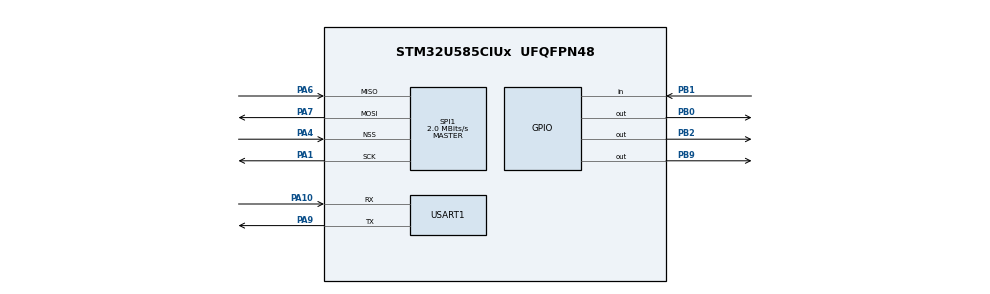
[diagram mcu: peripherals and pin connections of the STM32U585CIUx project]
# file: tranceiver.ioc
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CORTEX_M33_NS.userName=CORTEX_M33
Mcu.Family=STM32U5
Mcu.Name=STM32U585CIUx
Mcu.Package=UFQFPN48
NVIC.PriorityGroup=NVIC_PRIORITYGROUP_4
PA1.Mode=Full_Duplex_Master
PA1.Signal=SPI1_SCK
PA10.Mode=Asynchronous
PA10.Signal=USART1_RX
PA4.Mode=NSS_Signal_Hard_Input
PA4.Signal=SPI1_NSS
PA6.Mode=Full_Duplex_Master
PA6.Signal=SPI1_MISO
PA7.Mode=Full_Duplex_Master
PA7.Signal=SPI1_MOSI
PA9.Mode=Asynchronous
PA9.Signal=USART1_TX
PB0.Signal=GPIO_Output
PB1.Signal=GPIO_Input
PB2.Signal=GPIO_Output
PB9.Signal=GPIO_Output
PC14-OSC32_IN\ (PC14).Mode=LSE-External-Oscillator
PC14-OSC32_IN\ (PC14).Signal=RCC_OSC32_IN
PC15-OSC32_OUT\ (PC15).Mode=LSE-External-Oscillator
PC15-OSC32_OUT\ (PC15).Signal=RCC_OSC32_OUT
PH0-OSC_IN\ (PH0).Mode=HSE-External-Oscillator
PH0-OSC_IN\ (PH0).Signal=RCC_OSC_IN
PH1-OSC_OUT\ (PH1).Mode=HSE-External-Oscillator
PH1-OSC_OUT\ (PH1).Signal=RCC_OSC_OUT
ProjectManager.HeapSize=0x200
ProjectManager.StackSize=0x400
ProjectManager.TargetToolchain=EWARM V9.20
RCC.ADCFreq_Value=16000000
RCC.EPOD_VALUE=4000000
RCC.HSE_VALUE=16000000
RCC.HSI48_VALUE=48000000
RCC.HSI_VALUE=16000000
RCC.LSIDIV_VALUE=32000
RCC.MSI_VALUE=4000000
RCC.USBFreq_Value=48000000
RCC.VCOOutputFreq_Value=516000000
SPI1.CalculateBaudRate=2.0 MBits/s
SPI1.Direction=SPI_DIRECTION_2LINES
SPI1.Mode=SPI_MODE_MASTER
SPI1.VirtualNSS=VM_NSSHARD
SPI1.VirtualType=VM_MASTER
USART1.VirtualMode-Asynchronous=VM_ASYNC
VP_ICACHE_VS_ICACHE.Mode=DefaultMode
VP_LPBAMQUEUE_VS_QUEUE.Mode=QUEUEMODE
VP_LPBAM_VS_SIG1.Mode=SmartRun
VP_LPBAM_VS_SIG4.Mode=LPDMA1
VP_MEMORYMAP_VS_MEMORYMAP.Mode=CurAppReg
VP_PWR_VS_SECSignals.Mode=Security/Privilege
board=custom

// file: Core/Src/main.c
/* USER CODE BEGIN Header */
/**
  ******************************************************************************
  * @file           : main.c
  * @brief          : Main program body
  ******************************************************************************
  * @attention
  *
  * Copyright (c) 2026 STMicroelectronics.
  * All rights reserved.
  *
  * This software is licensed under terms that can be found in the LICENSE file
  * in the root directory of this software component.
  * If no LICENSE file comes with this software, it is provided AS-IS.
  *
  ******************************************************************************
  */
/* USER CODE END Header */
#include "main.h"

SPI_HandleTypeDef hspi1;

UART_HandleTypeDef huart1;

void SystemClock_Config(void);
static void MX_GPIO_Init(void);
static void MX_SPI1_Init(void);
static void MX_USART1_UART_Init(void);
static void MX_ICACHE_Init(void);

int main(void)
{

  /* MCU Configuration--------------------------------------------------------*/

  /* Reset of all peripherals, Initializes the Flash interface and the Systick. */
  HAL_Init();

  /* Configure the system clock */
  SystemClock_Config();

  /* Initialize all configured peripherals */
  MX_GPIO_Init();
  MX_SPI1_Init();
  MX_USART1_UART_Init();
  MX_ICACHE_Init();

  /* Infinite loop */
  while (1)
  {

  }
}

void SystemClock_Config(void)
{
  RCC_OscInitTypeDef RCC_OscInitStruct = {0};
  RCC_ClkInitTypeDef RCC_ClkInitStruct = {0};

  /** Configure the main internal regulator output voltage
  */
  if (HAL_PWREx_ControlVoltageScaling(PWR_REGULATOR_VOLTAGE_SCALE4) != HAL_OK)
  {
    Error_Handler();
  }

  /** Initializes the CPU, AHB and APB buses clocks
  */
  RCC_OscInitStruct.OscillatorType = RCC_OSCILLATORTYPE_MSI;
  RCC_OscInitStruct.MSIState = RCC_MSI_ON;
  RCC_OscInitStruct.MSICalibrationValue = RCC_MSICALIBRATION_DEFAULT;
  RCC_OscInitStruct.MSIClockRange = RCC_MSIRANGE_4;
  RCC_OscInitStruct.PLL.PLLState = RCC_PLL_NONE;
  if (HAL_RCC_OscConfig(&RCC_OscInitStruct) != HAL_OK)
  {
    Error_Handler();
  }

  /** Initializes the CPU, AHB and APB buses clocks
  */
  RCC_ClkInitStruct.ClockType = RCC_CLOCKTYPE_HCLK|RCC_CLOCKTYPE_SYSCLK
                              |RCC_CLOCKTYPE_PCLK1|RCC_CLOCKTYPE_PCLK2
                              |RCC_CLOCKTYPE_PCLK3;
  RCC_ClkInitStruct.SYSCLKSource = RCC_SYSCLKSOURCE_MSI;
  RCC_ClkInitStruct.AHBCLKDivider = RCC_SYSCLK_DIV1;
  RCC_ClkInitStruct.APB1CLKDivider = RCC_HCLK_DIV1;
  RCC_ClkInitStruct.APB2CLKDivider = RCC_HCLK_DIV1;
  RCC_ClkInitStruct.APB3CLKDivider = RCC_HCLK_DIV1;

  if (HAL_RCC_ClockConfig(&RCC_ClkInitStruct, FLASH_LATENCY_0) != HAL_OK)
  {
    Error_Handler();
  }
}

static void MX_ICACHE_Init(void)
{

  /** Enable instruction cache (default 2-ways set associative cache)
  */
  if (HAL_ICACHE_Enable() != HAL_OK)
  {
    Error_Handler();
  }

}

static void MX_SPI1_Init(void)
{

  SPI_AutonomousModeConfTypeDef HAL_SPI_AutonomousMode_Cfg_Struct = {0};

  /* SPI1 parameter configuration*/
  hspi1.Instance = SPI1;
  hspi1.Init.Mode = SPI_MODE_MASTER;
  hspi1.Init.Direction = SPI_DIRECTION_2LINES;
  hspi1.Init.DataSize = SPI_DATASIZE_4BIT;
  hspi1.Init.CLKPolarity = SPI_POLARITY_LOW;
  hspi1.Init.CLKPhase = SPI_PHASE_1EDGE;
  hspi1.Init.NSS = SPI_NSS_HARD_OUTPUT;
  hspi1.Init.BaudRatePrescaler = SPI_BAUDRATEPRESCALER_2;
  hspi1.Init.FirstBit = SPI_FIRSTBIT_MSB;
  hspi1.Init.TIMode = SPI_TIMODE_DISABLE;
  hspi1.Init.CRCCalculation = SPI_CRCCALCULATION_DISABLE;
  hspi1.Init.CRCPolynomial = 0x7;
  hspi1.Init.NSSPMode = SPI_NSS_PULSE_ENABLE;
  hspi1.Init.NSSPolarity = SPI_NSS_POLARITY_LOW;
  hspi1.Init.FifoThreshold = SPI_FIFO_THRESHOLD_01DATA;
  hspi1.Init.MasterSSIdleness = SPI_MASTER_SS_IDLENESS_00CYCLE;
  hspi1.Init.MasterInterDataIdleness = SPI_MASTER_INTERDATA_IDLENESS_00CYCLE;
  hspi1.Init.MasterReceiverAutoSusp = SPI_MASTER_RX_AUTOSUSP_DISABLE;
  hspi1.Init.MasterKeepIOState = SPI_MASTER_KEEP_IO_STATE_DISABLE;
  hspi1.Init.IOSwap = SPI_IO_SWAP_DISABLE;
  hspi1.Init.ReadyMasterManagement = SPI_RDY_MASTER_MANAGEMENT_INTERNALLY;
  hspi1.Init.ReadyPolarity = SPI_RDY_POLARITY_HIGH;
  if (HAL_SPI_Init(&hspi1) != HAL_OK)
  {
    Error_Handler();
  }
  HAL_SPI_AutonomousMode_Cfg_Struct.TriggerState = SPI_AUTO_MODE_DISABLE;
  HAL_SPI_AutonomousMode_Cfg_Struct.TriggerSelection = SPI_GRP1_GPDMA_CH0_TCF_TRG;
  HAL_SPI_AutonomousMode_Cfg_Struct.TriggerPolarity = SPI_TRIG_POLARITY_RISING;
  if (HAL_SPIEx_SetConfigAutonomousMode(&hspi1, &HAL_SPI_AutonomousMode_Cfg_Struct) != HAL_OK)
  {
    Error_Handler();
  }

}

static void MX_USART1_UART_Init(void)
{

  huart1.Instance = USART1;
  huart1.Init.BaudRate = 115200;
  huart1.Init.WordLength = UART_WORDLENGTH_8B;
  huart1.Init.StopBits = UART_STOPBITS_1;
  huart1.Init.Parity = UART_PARITY_NONE;
  huart1.Init.Mode = UART_MODE_TX_RX;
  huart1.Init.HwFlowCtl = UART_HWCONTROL_NONE;
  huart1.Init.OverSampling = UART_OVERSAMPLING_16;
  huart1.Init.OneBitSampling = UART_ONE_BIT_SAMPLE_DISABLE;
  huart1.Init.ClockPrescaler = UART_PRESCALER_DIV1;
  huart1.AdvancedInit.AdvFeatureInit = UART_ADVFEATURE_NO_INIT;
  if (HAL_UART_Init(&huart1) != HAL_OK)
  {
    Error_Handler();
  }
  if (HAL_UARTEx_SetTxFifoThreshold(&huart1, UART_TXFIFO_THRESHOLD_1_8) != HAL_OK)
  {
    Error_Handler();
  }
  if (HAL_UARTEx_SetRxFifoThreshold(&huart1, UART_RXFIFO_THRESHOLD_1_8) != HAL_OK)
  {
    Error_Handler();
  }
  if (HAL_UARTEx_DisableFifoMode(&huart1) != HAL_OK)
  {
    Error_Handler();
  }

}

static void MX_GPIO_Init(void)
{
  GPIO_InitTypeDef GPIO_InitStruct = {0};

  /* GPIO Ports Clock Enable */
  __HAL_RCC_GPIOC_CLK_ENABLE();
  __HAL_RCC_GPIOH_CLK_ENABLE();
  __HAL_RCC_GPIOA_CLK_ENABLE();
  __HAL_RCC_GPIOB_CLK_ENABLE();

  /*Configure GPIO pin Output Level */
  HAL_GPIO_WritePin(GPIOB, GPIO_PIN_0|GPIO_PIN_2, GPIO_PIN_RESET);

  /*Configure GPIO pin Output Level */
  HAL_GPIO_WritePin(GPIOA, GPIO_PIN_14|GPIO_PIN_15, GPIO_PIN_RESET);

  /*Configure GPIO pins : PB0 PB2 */
  GPIO_InitStruct.Pin = GPIO_PIN_0|GPIO_PIN_2;
  GPIO_InitStruct.Mode = GPIO_MODE_OUTPUT_PP;
  GPIO_InitStruct.Pull = GPIO_NOPULL;
  GPIO_InitStruct.Speed = GPIO_SPEED_FREQ_LOW;
  HAL_GPIO_Init(GPIOB, &GPIO_InitStruct);

  /*Configure GPIO pin : PB1 */
  GPIO_InitStruct.Pin = GPIO_PIN_1;
  GPIO_InitStruct.Mode = GPIO_MODE_INPUT;
  GPIO_InitStruct.Pull = GPIO_NOPULL;
  HAL_GPIO_Init(GPIOB, &GPIO_InitStruct);

  /*Configure GPIO pins : PA14 PA15 */
  GPIO_InitStruct.Pin = GPIO_PIN_14|GPIO_PIN_15;
  GPIO_InitStruct.Mode = GPIO_MODE_OUTPUT_PP;
  GPIO_InitStruct.Pull = GPIO_NOPULL;
  GPIO_InitStruct.Speed = GPIO_SPEED_FREQ_LOW;
  HAL_GPIO_Init(GPIOA, &GPIO_InitStruct);

}

void Error_Handler(void)
{
  __disable_irq();
  while (1)
  {
  }
}
